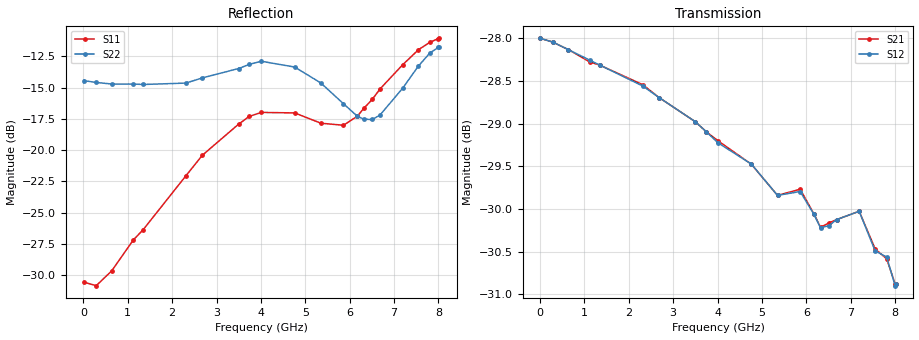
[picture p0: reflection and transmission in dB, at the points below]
! DEVICE ID: PE43712
! File Path: z:\PE43713\PE43713_CHAR_NOM_04292014\AMB\3p300\LS_ATT_26p75dB\PE43713_AMB_3p300V_3p000V_0p000V_LS_ATT_26p75dB_S2P_SN_10_A0139A.s2p
! Serial: 10
! Lot: A0139A
! Temp: 25C
! VDD: 3.300
! VSS: 0.000
! Control_Hi: 3.000
! Control_Lo: 0.000
! Attenuation Step: 26.75dB
! Port 1: RF1
! Port 2: RF2
! ThroughPath:1-2
! IDD: 0.000145201
! ISS: -2.267e-007
#  Hz  S  RI  R  50
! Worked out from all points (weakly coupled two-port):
!   801 points, 10 MHz to 8.01 GHz, reference 50 ohm
!   highest |S21| = -28.00 dB at 10 MHz (marker M1); lowest = -30.9 dB at 8 GHz (marker M2)
!   lowest |S11| = -30.9 dB at 290 MHz (marker M3), VSWR 1.06, Z = 47.4 + j1.03 ohm
!   |S11| at or under -10 dB: start of sweep to end of sweep
!   |S22| runs from -17.6 to -11.8 dB; largest |S21 - S12| = 0.00015
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1e7  -0.0296 0.000757  0.0398 -0.000176  0.0398 -0.000166  -0.1896 0.00125
2.9e8  -0.0265 0.0109  0.0394 -0.00394  0.0394 -0.00396  -0.1854 0.0195
6.4e8  -0.0234 0.0231  0.0383 -0.00835  0.0383 -0.00834  -0.1792 0.0408
1.12e9  -0.0179 0.0397  0.036 -0.0138  0.0361 -0.0138  -0.1702 0.0693
1.35e9  -0.0133 0.0462  0.0348 -0.0162  0.0348 -0.0162  -0.1641 0.081
2.31e9  0.0137 0.0777  0.0279 -0.0249  0.0279 -0.0248  -0.1281 0.134
2.68e9  0.0267 0.0915  0.0246 -0.0273  0.0246 -0.0273  -0.1114 0.1594
3.5e9  0.0457 0.1186  0.0167 -0.0314  0.0167 -0.0314  -0.0858 0.1939
3.74e9  0.0496 0.1271  0.0142 -0.0321  0.0142 -0.0321  -0.0828 0.2042
4.01e9  0.0534 0.131  0.0115 -0.0327  0.0115 -0.0326  -0.081 0.2117
4.76e9  0.0637 0.1256  0.00439 -0.0333  0.00444 -0.0333  -0.0644 0.205
5.35e9  0.0803 0.0998  -0.000518 -0.0322  -0.000488 -0.0322  -0.0471 0.1795
5.86e9  0.1039 0.0707  -0.0049 -0.0321  -0.0049 -0.032  -0.00956 0.1529
6.17e9  0.1241 0.0568  -0.00829 -0.0303  -0.0082 -0.0303  0.0214 0.135
6.32e9  0.1375 0.0522  -0.00868 -0.0296  -0.0086 -0.0296  0.04 0.1267
6.51e9  0.1525 0.0471  -0.00963 -0.0295  -0.00957 -0.0294  0.0621 0.1171
6.68e9  0.1698 0.0437  -0.0109 -0.0292  -0.0109 -0.0292  0.0836 0.1097
7.19e9  0.2155 0.0398  -0.0161 -0.0271  -0.0161 -0.0271  0.1411 0.106
7.55e9  0.2484 0.0434  -0.0182 -0.0238  -0.0182 -0.0237  0.185 0.1136
7.81e9  0.2659 0.0482  -0.0194 -0.0223  -0.0194 -0.0224  0.2125 0.1218
8e9  0.2746 0.0517  -0.0196 -0.0208  -0.0195 -0.0208  0.2254 0.1247
8.01e9  0.275 0.0522  -0.0196 -0.0208  -0.0196 -0.0208  0.2261 0.1247
